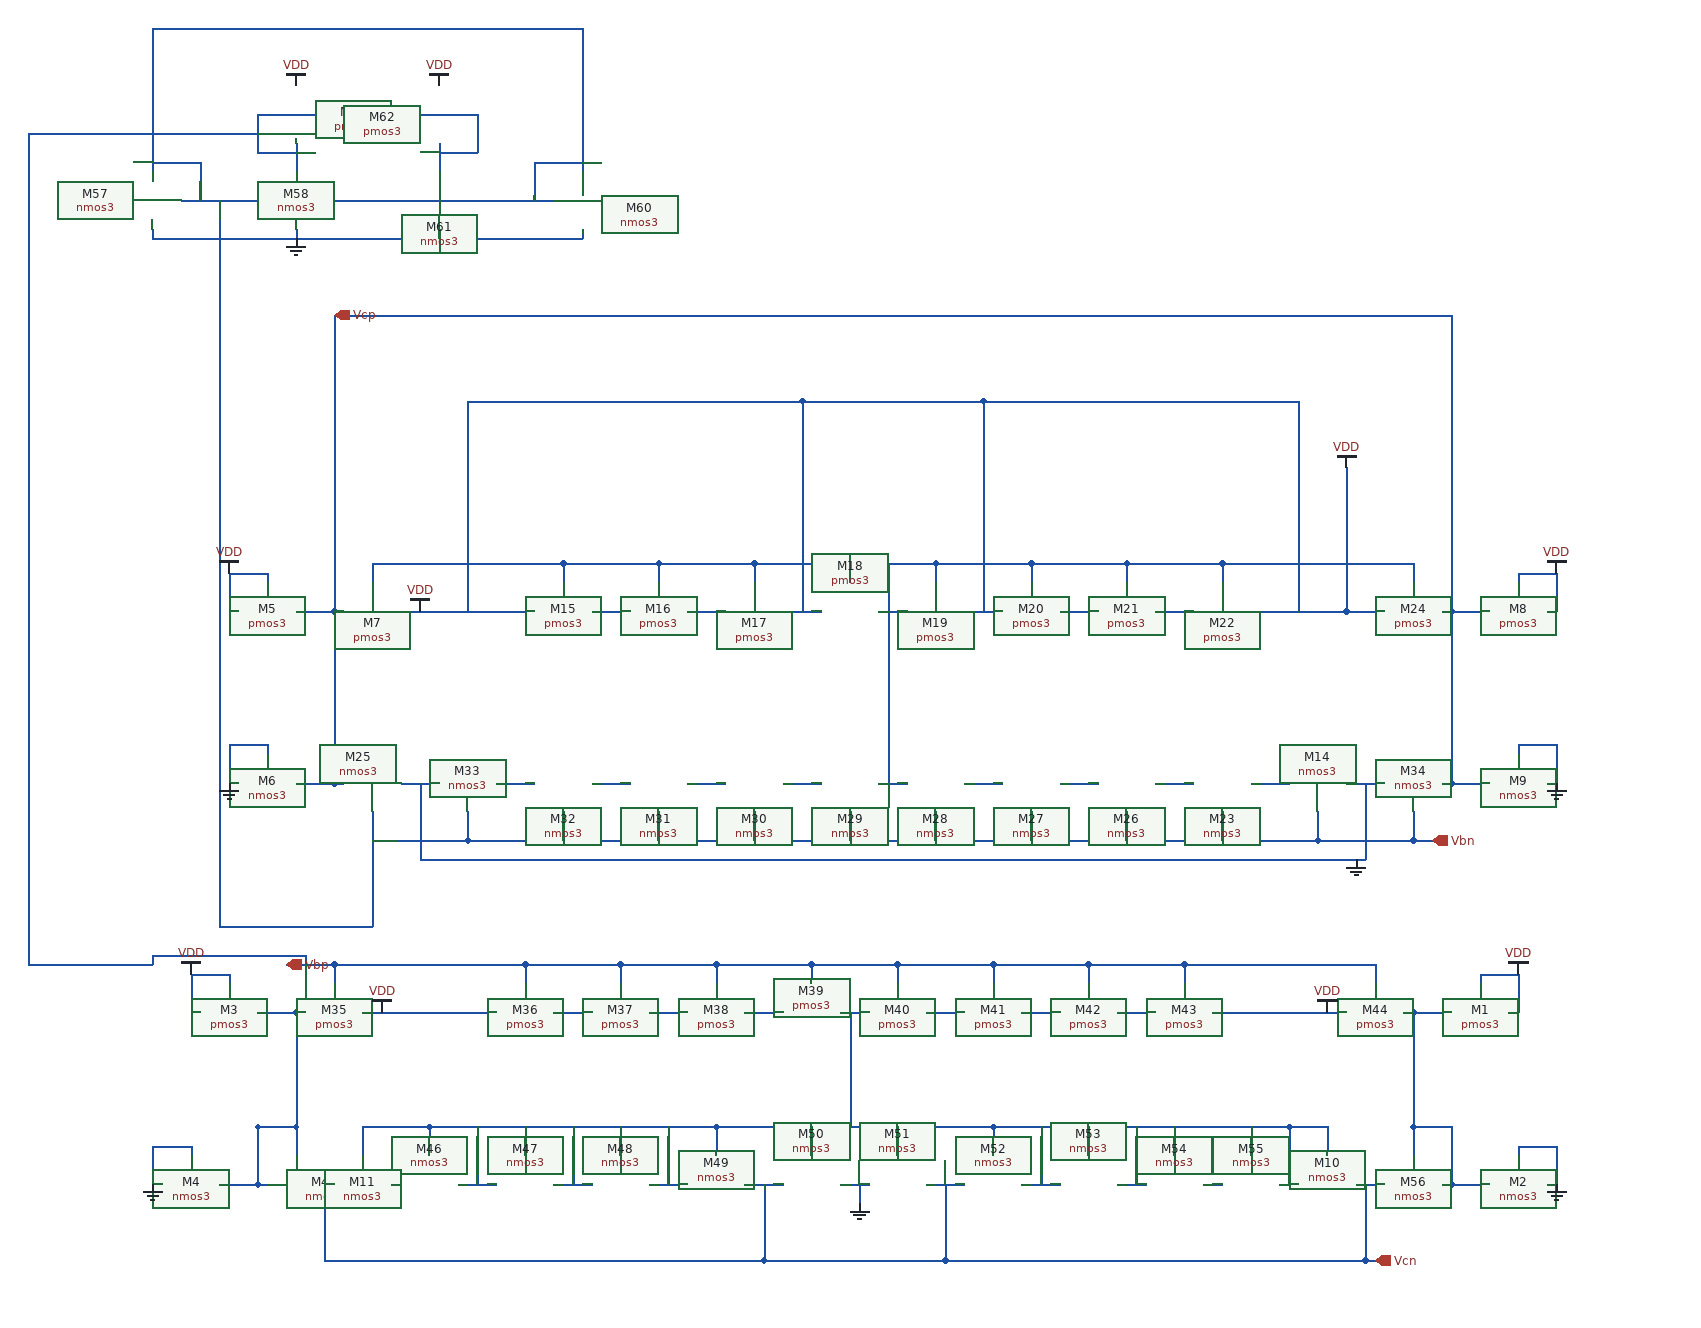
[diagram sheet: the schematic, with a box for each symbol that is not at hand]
v {xschem version=3.4.3 file_version=1.2
}
G {}
K {}
V {}
S {}
E {}
N 920 -40 960 -40 {
lab=VDD}
N 890 -90 890 -70 {
lab=VDD}
N 990 -90 1080 -90 {
lab=VDD}
N 1020 -40 1050 -40 {
lab=VDD}
N 1050 -40 1060 -40 {
lab=VDD}
N 1090 -90 1090 -70 {
lab=VDD}
N 1080 -90 1090 -90 {
lab=VDD}
N 1220 -40 1260 -40 {
lab=#net1}
N 1190 -90 1190 -70 {
lab=VDD}
N 1190 -90 1290 -90 {
lab=VDD}
N 1290 -90 1290 -70 {
lab=VDD}
N 1290 -90 1380 -90 {
lab=VDD}
N 1320 -40 1350 -40 {
lab=VDD}
N 1350 -40 1360 -40 {
lab=VDD}
N 1390 -90 1390 -70 {
lab=VDD}
N 1380 -90 1390 -90 {
lab=VDD}
N 1120 -40 1160 -40 {
lab=#net2}
N 1090 -90 1190 -90 {
lab=VDD}
N 1510 -40 1550 -40 {
lab=VDD}
N 1480 -90 1480 -70 {
lab=VDD}
N 1480 -90 1580 -90 {
lab=VDD}
N 1580 -90 1580 -70 {
lab=VDD}
N 1580 -90 1670 -90 {
lab=VDD}
N 1610 -40 1640 -40 {
lab=#net3}
N 1640 -40 1650 -40 {
lab=#net3}
N 1680 -90 1680 -70 {
lab=VDD}
N 1670 -90 1680 -90 {
lab=VDD}
N 1810 -40 1850 -40 {
lab=VDD}
N 1780 -90 1780 -70 {
lab=VDD}
N 1780 -90 1880 -90 {
lab=VDD}
N 1910 -40 1940 -40 {
lab=VDD}
N 1940 -40 1950 -40 {
lab=VDD}
N 1980 -90 1980 -70 {
lab=VDD}
N 1970 -90 1980 -90 {
lab=VDD}
N 1710 -40 1750 -40 {
lab=#net4}
N 1680 -90 1780 -90 {
lab=VDD}
N 1420 -40 1450 -40 {
lab=VDD}
N 1390 -90 1480 -90 {
lab=VDD}
N 1930 -90 1970 -90 {
lab=VDD}
N 890 -90 940 -90 {
lab=VDD}
N 1880 -90 1930 -90 {
lab=VDD}
N 940 -90 990 -90 {
lab=VDD}
N 960 -40 1020 -40 {
lab=VDD}
N 1850 -40 1910 -40 {
lab=VDD}
N 1220 140 1260 140 {
lab=#net5}
N 1120 140 1160 140 {
lab=#net6}
N 1020 140 1060 140 {
lab=#net7}
N 1320 140 1360 140 {
lab=#net8}
N 920 140 960 140 {
lab=GND}
N 940 140 940 220 {
lab=GND}
N 940 220 1340 220 {
lab=GND}
N 1810 140 1850 140 {
lab=#net9}
N 1710 140 1750 140 {
lab=#net10}
N 1610 140 1650 140 {
lab=#net11}
N 1910 140 1950 140 {
lab=GND}
N 1510 140 1550 140 {
lab=#net12}
N 1930 140 1930 220 {
lab=GND}
N 1420 140 1450 140 {
lab=VDD}
N 1340 220 1530 220 {
lab=GND}
N 2010 140 2020 140 {
lab=Vcp}
N 850 140 860 140 {
lab=Vcp}
N 850 -40 860 -40 {
lab=Vcp}
N 2010 -40 2020 -40 {
lab=Vcp}
N 880 380 920 380 {
lab=VDD}
N 850 330 850 350 {
lab=Vbp}
N 950 330 1040 330 {
lab=Vbp}
N 980 380 1010 380 {
lab=VDD}
N 1010 380 1020 380 {
lab=VDD}
N 1050 330 1050 350 {
lab=Vbp}
N 1040 330 1050 330 {
lab=Vbp}
N 1180 380 1220 380 {
lab=#net13}
N 1150 330 1150 350 {
lab=Vbp}
N 1150 330 1250 330 {
lab=Vbp}
N 1250 330 1250 350 {
lab=Vbp}
N 1250 330 1340 330 {
lab=Vbp}
N 1280 380 1310 380 {
lab=#net14}
N 1310 380 1320 380 {
lab=#net14}
N 1350 330 1350 350 {
lab=Vbp}
N 1340 330 1350 330 {
lab=Vbp}
N 1080 380 1120 380 {
lab=#net15}
N 1050 330 1150 330 {
lab=Vbp}
N 1470 380 1510 380 {
lab=#net16}
N 1440 330 1440 350 {
lab=Vbp}
N 1440 330 1540 330 {
lab=Vbp}
N 1540 330 1540 350 {
lab=Vbp}
N 1540 330 1630 330 {
lab=Vbp}
N 1570 380 1600 380 {
lab=#net17}
N 1600 380 1610 380 {
lab=#net17}
N 1640 330 1640 350 {
lab=Vbp}
N 1630 330 1640 330 {
lab=Vbp}
N 1770 380 1810 380 {
lab=VDD}
N 1740 330 1740 350 {
lab=Vbp}
N 1740 330 1840 330 {
lab=Vbp}
N 1870 380 1900 380 {
lab=VDD}
N 1900 380 1910 380 {
lab=VDD}
N 1940 330 1940 350 {
lab=Vbp}
N 1930 330 1940 330 {
lab=Vbp}
N 1670 380 1710 380 {
lab=#net18}
N 1640 330 1740 330 {
lab=Vbp}
N 1380 380 1410 380 {
lab=#net19}
N 1350 330 1440 330 {
lab=Vbp}
N 1890 330 1930 330 {
lab=Vbp}
N 850 330 900 330 {
lab=Vbp}
N 1840 330 1890 330 {
lab=Vbp}
N 900 330 950 330 {
lab=Vbp}
N 920 380 980 380 {
lab=VDD}
N 1810 380 1870 380 {
lab=VDD}
N 1180 560 1220 560 {
lab=#net19}
N 1080 560 1120 560 {
lab=#net19}
N 980 560 1020 560 {
lab=#net19}
N 1280 560 1320 560 {
lab=Vcn}
N 900 640 1300 640 {
lab=Vcn}
N 1300 560 1300 640 {
lab=Vcn}
N 950 500 950 530 {
lab=#net19}
N 950 500 1250 500 {
lab=#net19}
N 1250 500 1250 530 {
lab=#net19}
N 1570 560 1610 560 {
lab=#net19}
N 1470 560 1510 560 {
lab=Vcn}
N 1490 560 1490 640 {
lab=Vcn}
N 1490 640 1890 640 {
lab=Vcn}
N 1930 560 1930 640 {
lab=Vcn}
N 1540 500 1540 530 {
lab=#net19}
N 1380 560 1410 560 {
lab=GND}
N 1400 560 1400 580 {
lab=GND}
N 1300 640 1490 640 {
lab=Vcn}
N 1250 500 1540 500 {
lab=#net19}
N 1980 500 1980 530 {
lab=#net20}
N 1980 500 2020 500 {
lab=#net20}
N 2010 560 2020 560 {
lab=#net20}
N 2020 500 2020 560 {
lab=#net20}
N 810 500 810 530 {
lab=#net21}
N 770 500 810 500 {
lab=#net21}
N 770 560 780 560 {
lab=#net21}
N 770 500 770 560 {
lab=#net21}
N 1980 380 1980 500 {
lab=#net20}
N 810 380 820 380 {
lab=#net21}
N 810 380 810 500 {
lab=#net21}
N 1970 380 1980 380 {
lab=#net20}
N 1350 500 1350 530 {
lab=#net19}
N 1440 500 1440 530 {
lab=#net19}
N 1390 380 1390 500 {
lab=#net19}
N 800 330 850 330 {
lab=Vbp}
N 1930 640 1940 640 {
lab=Vcn}
N 660 -530 660 -500 {
lab=Vbn}
N 660 -440 660 -430 {
lab=GND}
N 810 -440 810 -430 {
lab=GND}
N 690 -470 780 -470 {
lab=Vbn}
N 710 -510 710 -470 {
lab=Vbn}
N 660 -510 710 -510 {
lab=Vbn}
N 810 -530 810 -500 {
lab=Vbp}
N 770 -520 810 -520 {
lab=Vbp}
N 770 -560 770 -520 {
lab=Vbp}
N 770 -560 780 -560 {
lab=Vbp}
N 1110 -530 1110 -500 {
lab=Vbn}
N 1110 -440 1110 -430 {
lab=GND}
N 960 -440 960 -430 {
lab=GND}
N 990 -470 1080 -470 {
lab=Vbn}
N 1060 -510 1060 -470 {
lab=Vbn}
N 1060 -510 1110 -510 {
lab=Vbn}
N 960 -530 960 -500 {
lab=Vbp}
N 960 -520 1000 -520 {
lab=Vbp}
N 1000 -560 1000 -520 {
lab=Vbp}
N 990 -560 1000 -560 {
lab=Vbp}
N 780 -560 990 -560 {
lab=Vbp}
N 780 -470 990 -470 {
lab=Vbn}
N 1110 -650 1110 -530 {
lab=Vbn}
N 660 -650 1110 -650 {
lab=Vbn}
N 660 -650 660 -640 {
lab=Vbn}
N 660 -640 660 -530 {
lab=Vbn}
N 660 -430 1110 -430 {
lab=GND}
N 730 -470 730 290 {
lab=Vbn}
N 2020 560 2060 560 {
lab=#net20}
N 1980 380 2020 380 {
lab=#net20}
N 2050 340 2050 350 {
lab=VDD}
N 2050 340 2090 340 {
lab=VDD}
N 2090 340 2090 380 {
lab=VDD}
N 2080 380 2090 380 {
lab=VDD}
N 2090 520 2090 530 {
lab=GND}
N 2090 520 2130 520 {
lab=GND}
N 2130 520 2130 560 {
lab=GND}
N 2120 560 2130 560 {
lab=GND}
N 770 500 770 560 {
lab=#net21}
N 810 380 810 500 {
lab=#net21}
N 730 560 770 560 {
lab=#net21}
N 770 380 810 380 {
lab=#net21}
N 740 340 740 350 {
lab=VDD}
N 700 340 740 340 {
lab=VDD}
N 700 340 700 380 {
lab=VDD}
N 700 380 710 380 {
lab=VDD}
N 700 520 700 530 {
lab=GND}
N 660 520 700 520 {
lab=GND}
N 660 520 660 560 {
lab=GND}
N 660 560 670 560 {
lab=GND}
N 850 80 850 140 {
lab=Vcp}
N 810 140 850 140 {
lab=Vcp}
N 810 -40 850 -40 {
lab=Vcp}
N 780 -80 780 -70 {
lab=VDD}
N 740 -80 780 -80 {
lab=VDD}
N 740 -80 740 -40 {
lab=VDD}
N 740 -40 750 -40 {
lab=VDD}
N 780 100 780 110 {
lab=GND}
N 740 100 780 100 {
lab=GND}
N 740 100 740 140 {
lab=GND}
N 740 140 750 140 {
lab=GND}
N 2020 -40 2020 80 {
lab=Vcp}
N 2020 140 2060 140 {
lab=Vcp}
N 2020 -40 2060 -40 {
lab=Vcp}
N 2090 -80 2090 -70 {
lab=VDD}
N 2090 -80 2130 -80 {
lab=VDD}
N 2130 -80 2130 -40 {
lab=VDD}
N 2120 -40 2130 -40 {
lab=VDD}
N 2090 100 2090 110 {
lab=GND}
N 2090 100 2130 100 {
lab=GND}
N 2130 100 2130 140 {
lab=GND}
N 2120 140 2130 140 {
lab=GND}
N 1000 500 1000 560 {
lab=#net19}
N 1050 500 1050 530 {
lab=#net19}
N 1150 500 1150 530 {
lab=#net19}
N 1100 500 1100 560 {
lab=#net19}
N 1200 500 1200 560 {
lab=#net19}
N 1640 500 1640 530 {
lab=#net19}
N 1590 500 1590 560 {
lab=#net19}
N 1690 500 1690 560 {
lab=#net19}
N 1810 500 1810 530 {
lab=#net19}
N 1540 500 1820 500 {
lab=#net19}
N 1850 500 1850 560 {
lab=#net19}
N 1850 500 1880 500 {
lab=#net19}
N 1820 500 1850 500 {
lab=#net19}
N 1890 640 1930 640 {
lab=Vcn}
N 840 640 900 640 {
lab=Vcn}
N 840 560 840 640 {
lab=Vcn}
N 1430 80 1430 140 {
lab=VDD}
N 990 200 1880 200 {
lab=Vbn}
N 1880 200 1980 200 {
lab=Vbn}
N 1980 200 2000 200 {
lab=Vbn}
N 1530 220 1930 220 {
lab=GND}
N 1430 -90 1430 80 {
lab=VDD}
N 1910 -190 1910 -40 {
lab=VDD}
N 990 -250 990 -40 {
lab=VDD}
N 1340 -260 1340 -40 {
lab=VDD}
N 990 -260 1340 -260 {
lab=VDD}
N 990 -260 990 -250 {
lab=VDD}
N 1530 -260 1530 -40 {
lab=VDD}
N 1530 -260 1860 -260 {
lab=VDD}
N 1860 -260 1860 -40 {
lab=VDD}
N 1340 -260 1530 -260 {
lab=VDD}
N 850 -350 850 -40 {
lab=Vcp}
N 850 -350 2010 -350 {
lab=Vcp}
N 2010 -350 2020 -350 {
lab=Vcp}
N 2020 -350 2020 -40 {
lab=Vcp}
N 890 170 890 240 {
lab=Vbn}
N 730 290 890 290 {
lab=Vbn}
N 530 -540 770 -540 {
lab=Vbp}
N 530 -540 530 330 {
lab=Vbp}
N 530 330 660 330 {
lab=Vbp}
N 660 320 660 330 {
lab=Vbp}
N 660 320 820 320 {
lab=Vbp}
N 820 320 820 330 {
lab=Vbp}
N 890 200 980 200 {
lab=Vbn}
N 980 200 990 200 {
lab=Vbn}
N 990 170 990 200 {
lab=Vbn}
N 1090 170 1090 200 {
lab=Vbn}
N 1190 170 1190 200 {
lab=Vbn}
N 1290 170 1290 200 {
lab=Vbn}
N 1390 170 1390 200 {
lab=Vbn}
N 1480 170 1480 200 {
lab=Vbn}
N 1580 170 1580 200 {
lab=Vbn}
N 1680 170 1680 200 {
lab=Vbn}
N 1780 170 1780 200 {
lab=Vbn}
N 1880 170 1880 200 {
lab=Vbn}
N 1980 170 1980 200 {
lab=Vbn}
N 850 -40 850 80 {
lab=Vcp}
N 2020 80 2020 140 {
lab=Vcp}
N 840 560 850 560 {
lab=Vcn}
N 910 560 920 560 {
lab=#net22}
N 880 500 880 530 {
lab=#net19}
N 880 500 950 500 {
lab=#net19}
N 1670 560 1700 560 {
lab=#net19}
N 1730 500 1730 530 {
lab=#net19}
N 1920 560 1950 560 {
lab=Vcn}
N 1890 500 1890 530 {
lab=#net19}
N 1880 500 1890 500 {
lab=#net19}
N 1840 560 1860 560 {
lab=#net19}
N 1760 560 1780 560 {
lab=#net23}
N 890 240 890 290 {
lab=Vbn}
C {madvlsi/pmos3.sym} 890 -40 1 0 {name=M7
L=0.5
W=12
body=VDD
nf=1
mult=1
ad="'int((nf+1)/2) * W/nf * 0.29'" 
pd="'2*int((nf+1)/2) * (W/nf + 0.29)'"
as="'int((nf+2)/2) * W/nf * 0.29'" 
ps="'2*int((nf+2)/2) * (W/nf + 0.29)'"
nrd="'0.29 / W'" nrs="'0.29 / W'"
sa=0 sb=0 sd=0
model=pfet_01v8
spiceprefix=X
}
C {madvlsi/pmos3.sym} 1090 -40 1 0 {name=M15
L=0.5
W=12
body=VDD
nf=1
mult=1
ad="'int((nf+1)/2) * W/nf * 0.29'" 
pd="'2*int((nf+1)/2) * (W/nf + 0.29)'"
as="'int((nf+2)/2) * W/nf * 0.29'" 
ps="'2*int((nf+2)/2) * (W/nf + 0.29)'"
nrd="'0.29 / W'" nrs="'0.29 / W'"
sa=0 sb=0 sd=0
model=pfet_01v8
spiceprefix=X
}
C {madvlsi/pmos3.sym} 1190 -40 1 0 {name=M16
L=0.5
W=12
body=VDD
nf=1
mult=1
ad="'int((nf+1)/2) * W/nf * 0.29'" 
pd="'2*int((nf+1)/2) * (W/nf + 0.29)'"
as="'int((nf+2)/2) * W/nf * 0.29'" 
ps="'2*int((nf+2)/2) * (W/nf + 0.29)'"
nrd="'0.29 / W'" nrs="'0.29 / W'"
sa=0 sb=0 sd=0
model=pfet_01v8
spiceprefix=X
}
C {madvlsi/pmos3.sym} 1290 -40 1 0 {name=M17
L=0.5
W=12
body=VDD
nf=1
mult=1
ad="'int((nf+1)/2) * W/nf * 0.29'" 
pd="'2*int((nf+1)/2) * (W/nf + 0.29)'"
as="'int((nf+2)/2) * W/nf * 0.29'" 
ps="'2*int((nf+2)/2) * (W/nf + 0.29)'"
nrd="'0.29 / W'" nrs="'0.29 / W'"
sa=0 sb=0 sd=0
model=pfet_01v8
spiceprefix=X
}
C {madvlsi/pmos3.sym} 1390 -40 1 0 {name=M18
L=0.5
W=12
body=VDD
nf=1
mult=1
ad="'int((nf+1)/2) * W/nf * 0.29'" 
pd="'2*int((nf+1)/2) * (W/nf + 0.29)'"
as="'int((nf+2)/2) * W/nf * 0.29'" 
ps="'2*int((nf+2)/2) * (W/nf + 0.29)'"
nrd="'0.29 / W'" nrs="'0.29 / W'"
sa=0 sb=0 sd=0
model=pfet_01v8
spiceprefix=X
}
C {madvlsi/pmos3.sym} 1480 -40 1 0 {name=M19
L=0.5
W=12
body=VDD
nf=1
mult=1
ad="'int((nf+1)/2) * W/nf * 0.29'" 
pd="'2*int((nf+1)/2) * (W/nf + 0.29)'"
as="'int((nf+2)/2) * W/nf * 0.29'" 
ps="'2*int((nf+2)/2) * (W/nf + 0.29)'"
nrd="'0.29 / W'" nrs="'0.29 / W'"
sa=0 sb=0 sd=0
model=pfet_01v8
spiceprefix=X
}
C {madvlsi/pmos3.sym} 1580 -40 1 0 {name=M20
L=0.5
W=12
body=VDD
nf=1
mult=1
ad="'int((nf+1)/2) * W/nf * 0.29'" 
pd="'2*int((nf+1)/2) * (W/nf + 0.29)'"
as="'int((nf+2)/2) * W/nf * 0.29'" 
ps="'2*int((nf+2)/2) * (W/nf + 0.29)'"
nrd="'0.29 / W'" nrs="'0.29 / W'"
sa=0 sb=0 sd=0
model=pfet_01v8
spiceprefix=X
}
C {madvlsi/pmos3.sym} 1680 -40 1 0 {name=M21
L=0.5
W=12
body=VDD
nf=1
mult=1
ad="'int((nf+1)/2) * W/nf * 0.29'" 
pd="'2*int((nf+1)/2) * (W/nf + 0.29)'"
as="'int((nf+2)/2) * W/nf * 0.29'" 
ps="'2*int((nf+2)/2) * (W/nf + 0.29)'"
nrd="'0.29 / W'" nrs="'0.29 / W'"
sa=0 sb=0 sd=0
model=pfet_01v8
spiceprefix=X
}
C {madvlsi/pmos3.sym} 1780 -40 1 0 {name=M22
L=0.5
W=12
body=VDD
nf=1
mult=1
ad="'int((nf+1)/2) * W/nf * 0.29'" 
pd="'2*int((nf+1)/2) * (W/nf + 0.29)'"
as="'int((nf+2)/2) * W/nf * 0.29'" 
ps="'2*int((nf+2)/2) * (W/nf + 0.29)'"
nrd="'0.29 / W'" nrs="'0.29 / W'"
sa=0 sb=0 sd=0
model=pfet_01v8
spiceprefix=X
}
C {madvlsi/pmos3.sym} 1980 -40 1 0 {name=M24
L=0.5
W=12
body=VDD
nf=1
mult=1
ad="'int((nf+1)/2) * W/nf * 0.29'" 
pd="'2*int((nf+1)/2) * (W/nf + 0.29)'"
as="'int((nf+2)/2) * W/nf * 0.29'" 
ps="'2*int((nf+2)/2) * (W/nf + 0.29)'"
nrd="'0.29 / W'" nrs="'0.29 / W'"
sa=0 sb=0 sd=0
model=pfet_01v8
spiceprefix=X
}
C {madvlsi/vdd.sym} 940 -40 0 0 {name=l9 lab=VDD}
C {madvlsi/nmos3.sym} 890 140 3 0 {name=M25
L=0.5
W=12
body=GND
nf=1
mult=1
ad="'int((nf+1)/2) * W/nf * 0.29'" 
pd="'2*int((nf+1)/2) * (W/nf + 0.29)'"
as="'int((nf+2)/2) * W/nf * 0.29'" 
ps="'2*int((nf+2)/2) * (W/nf + 0.29)'"
nrd="'0.29 / W'" nrs="'0.29 / W'"
sa=0 sb=0 sd=0
model=nfet_01v8
spiceprefix=X
}
C {madvlsi/nmos3.sym} 1880 140 3 0 {name=M14
L=0.5
W=12
body=GND
nf=1
mult=1
ad="'int((nf+1)/2) * W/nf * 0.29'" 
pd="'2*int((nf+1)/2) * (W/nf + 0.29)'"
as="'int((nf+2)/2) * W/nf * 0.29'" 
ps="'2*int((nf+2)/2) * (W/nf + 0.29)'"
nrd="'0.29 / W'" nrs="'0.29 / W'"
sa=0 sb=0 sd=0
model=nfet_01v8
spiceprefix=X
}
C {madvlsi/nmos3.sym} 1780 140 3 0 {name=M23
L=0.5
W=12
body=GND
nf=1
mult=1
ad="'int((nf+1)/2) * W/nf * 0.29'" 
pd="'2*int((nf+1)/2) * (W/nf + 0.29)'"
as="'int((nf+2)/2) * W/nf * 0.29'" 
ps="'2*int((nf+2)/2) * (W/nf + 0.29)'"
nrd="'0.29 / W'" nrs="'0.29 / W'"
sa=0 sb=0 sd=0
model=nfet_01v8
spiceprefix=X
}
C {madvlsi/nmos3.sym} 1680 140 3 0 {name=M26
L=0.5
W=12
body=GND
nf=1
mult=1
ad="'int((nf+1)/2) * W/nf * 0.29'" 
pd="'2*int((nf+1)/2) * (W/nf + 0.29)'"
as="'int((nf+2)/2) * W/nf * 0.29'" 
ps="'2*int((nf+2)/2) * (W/nf + 0.29)'"
nrd="'0.29 / W'" nrs="'0.29 / W'"
sa=0 sb=0 sd=0
model=nfet_01v8
spiceprefix=X
}
C {madvlsi/nmos3.sym} 1580 140 3 0 {name=M27
L=0.5
W=12
body=GND
nf=1
mult=1
ad="'int((nf+1)/2) * W/nf * 0.29'" 
pd="'2*int((nf+1)/2) * (W/nf + 0.29)'"
as="'int((nf+2)/2) * W/nf * 0.29'" 
ps="'2*int((nf+2)/2) * (W/nf + 0.29)'"
nrd="'0.29 / W'" nrs="'0.29 / W'"
sa=0 sb=0 sd=0
model=nfet_01v8
spiceprefix=X
}
C {madvlsi/nmos3.sym} 1480 140 3 0 {name=M28
L=0.5
W=12
body=GND
nf=1
mult=1
ad="'int((nf+1)/2) * W/nf * 0.29'" 
pd="'2*int((nf+1)/2) * (W/nf + 0.29)'"
as="'int((nf+2)/2) * W/nf * 0.29'" 
ps="'2*int((nf+2)/2) * (W/nf + 0.29)'"
nrd="'0.29 / W'" nrs="'0.29 / W'"
sa=0 sb=0 sd=0
model=nfet_01v8
spiceprefix=X
}
C {madvlsi/nmos3.sym} 1390 140 3 0 {name=M29
L=0.5
W=12
body=GND
nf=1
mult=1
ad="'int((nf+1)/2) * W/nf * 0.29'" 
pd="'2*int((nf+1)/2) * (W/nf + 0.29)'"
as="'int((nf+2)/2) * W/nf * 0.29'" 
ps="'2*int((nf+2)/2) * (W/nf + 0.29)'"
nrd="'0.29 / W'" nrs="'0.29 / W'"
sa=0 sb=0 sd=0
model=nfet_01v8
spiceprefix=X
}
C {madvlsi/nmos3.sym} 1290 140 3 0 {name=M30
L=0.5
W=12
body=GND
nf=1
mult=1
ad="'int((nf+1)/2) * W/nf * 0.29'" 
pd="'2*int((nf+1)/2) * (W/nf + 0.29)'"
as="'int((nf+2)/2) * W/nf * 0.29'" 
ps="'2*int((nf+2)/2) * (W/nf + 0.29)'"
nrd="'0.29 / W'" nrs="'0.29 / W'"
sa=0 sb=0 sd=0
model=nfet_01v8
spiceprefix=X
}
C {madvlsi/nmos3.sym} 1190 140 3 0 {name=M31
L=0.5
W=12
body=GND
nf=1
mult=1
ad="'int((nf+1)/2) * W/nf * 0.29'" 
pd="'2*int((nf+1)/2) * (W/nf + 0.29)'"
as="'int((nf+2)/2) * W/nf * 0.29'" 
ps="'2*int((nf+2)/2) * (W/nf + 0.29)'"
nrd="'0.29 / W'" nrs="'0.29 / W'"
sa=0 sb=0 sd=0
model=nfet_01v8
spiceprefix=X
}
C {madvlsi/nmos3.sym} 1090 140 3 0 {name=M32
L=0.5
W=12
body=GND
nf=1
mult=1
ad="'int((nf+1)/2) * W/nf * 0.29'" 
pd="'2*int((nf+1)/2) * (W/nf + 0.29)'"
as="'int((nf+2)/2) * W/nf * 0.29'" 
ps="'2*int((nf+2)/2) * (W/nf + 0.29)'"
nrd="'0.29 / W'" nrs="'0.29 / W'"
sa=0 sb=0 sd=0
model=nfet_01v8
spiceprefix=X
}
C {madvlsi/nmos3.sym} 990 140 3 0 {name=M33
L=0.5
W=12
body=GND
nf=1
mult=1
ad="'int((nf+1)/2) * W/nf * 0.29'" 
pd="'2*int((nf+1)/2) * (W/nf + 0.29)'"
as="'int((nf+2)/2) * W/nf * 0.29'" 
ps="'2*int((nf+2)/2) * (W/nf + 0.29)'"
nrd="'0.29 / W'" nrs="'0.29 / W'"
sa=0 sb=0 sd=0
model=nfet_01v8
spiceprefix=X
}
C {madvlsi/nmos3.sym} 1980 140 3 0 {name=M34
L=0.5
W=12
body=GND
nf=1
mult=1
ad="'int((nf+1)/2) * W/nf * 0.29'" 
pd="'2*int((nf+1)/2) * (W/nf + 0.29)'"
as="'int((nf+2)/2) * W/nf * 0.29'" 
ps="'2*int((nf+2)/2) * (W/nf + 0.29)'"
nrd="'0.29 / W'" nrs="'0.29 / W'"
sa=0 sb=0 sd=0
model=nfet_01v8
spiceprefix=X
}
C {devices/opin.sym} 800 330 2 0 {name=p1 lab=Vbp}
C {devices/opin.sym} 1940 640 0 0 {name=p3 lab=Vcn}
C {madvlsi/pmos3.sym} 850 380 1 0 {name=M35
L=0.5
W=12
body=VDD
nf=1
mult=1
ad="'int((nf+1)/2) * W/nf * 0.29'" 
pd="'2*int((nf+1)/2) * (W/nf + 0.29)'"
as="'int((nf+2)/2) * W/nf * 0.29'" 
ps="'2*int((nf+2)/2) * (W/nf + 0.29)'"
nrd="'0.29 / W'" nrs="'0.29 / W'"
sa=0 sb=0 sd=0
model=pfet_01v8
spiceprefix=X
}
C {madvlsi/pmos3.sym} 1050 380 1 0 {name=M36
L=0.5
W=12
body=VDD
nf=1
mult=1
ad="'int((nf+1)/2) * W/nf * 0.29'" 
pd="'2*int((nf+1)/2) * (W/nf + 0.29)'"
as="'int((nf+2)/2) * W/nf * 0.29'" 
ps="'2*int((nf+2)/2) * (W/nf + 0.29)'"
nrd="'0.29 / W'" nrs="'0.29 / W'"
sa=0 sb=0 sd=0
model=pfet_01v8
spiceprefix=X
}
C {madvlsi/pmos3.sym} 1150 380 1 0 {name=M37
L=0.5
W=12
body=VDD
nf=1
mult=1
ad="'int((nf+1)/2) * W/nf * 0.29'" 
pd="'2*int((nf+1)/2) * (W/nf + 0.29)'"
as="'int((nf+2)/2) * W/nf * 0.29'" 
ps="'2*int((nf+2)/2) * (W/nf + 0.29)'"
nrd="'0.29 / W'" nrs="'0.29 / W'"
sa=0 sb=0 sd=0
model=pfet_01v8
spiceprefix=X
}
C {madvlsi/pmos3.sym} 1250 380 1 0 {name=M38
L=0.5
W=12
body=VDD
nf=1
mult=1
ad="'int((nf+1)/2) * W/nf * 0.29'" 
pd="'2*int((nf+1)/2) * (W/nf + 0.29)'"
as="'int((nf+2)/2) * W/nf * 0.29'" 
ps="'2*int((nf+2)/2) * (W/nf + 0.29)'"
nrd="'0.29 / W'" nrs="'0.29 / W'"
sa=0 sb=0 sd=0
model=pfet_01v8
spiceprefix=X
}
C {madvlsi/pmos3.sym} 1350 380 1 0 {name=M39
L=0.5
W=12
body=VDD
nf=1
mult=1
ad="'int((nf+1)/2) * W/nf * 0.29'" 
pd="'2*int((nf+1)/2) * (W/nf + 0.29)'"
as="'int((nf+2)/2) * W/nf * 0.29'" 
ps="'2*int((nf+2)/2) * (W/nf + 0.29)'"
nrd="'0.29 / W'" nrs="'0.29 / W'"
sa=0 sb=0 sd=0
model=pfet_01v8
spiceprefix=X
}
C {madvlsi/pmos3.sym} 1440 380 1 0 {name=M40
L=0.5
W=12
body=VDD
nf=1
mult=1
ad="'int((nf+1)/2) * W/nf * 0.29'" 
pd="'2*int((nf+1)/2) * (W/nf + 0.29)'"
as="'int((nf+2)/2) * W/nf * 0.29'" 
ps="'2*int((nf+2)/2) * (W/nf + 0.29)'"
nrd="'0.29 / W'" nrs="'0.29 / W'"
sa=0 sb=0 sd=0
model=pfet_01v8
spiceprefix=X
}
C {madvlsi/pmos3.sym} 1540 380 1 0 {name=M41
L=0.5
W=12
body=VDD
nf=1
mult=1
ad="'int((nf+1)/2) * W/nf * 0.29'" 
pd="'2*int((nf+1)/2) * (W/nf + 0.29)'"
as="'int((nf+2)/2) * W/nf * 0.29'" 
ps="'2*int((nf+2)/2) * (W/nf + 0.29)'"
nrd="'0.29 / W'" nrs="'0.29 / W'"
sa=0 sb=0 sd=0
model=pfet_01v8
spiceprefix=X
}
C {madvlsi/pmos3.sym} 1640 380 1 0 {name=M42
L=0.5
W=12
body=VDD
nf=1
mult=1
ad="'int((nf+1)/2) * W/nf * 0.29'" 
pd="'2*int((nf+1)/2) * (W/nf + 0.29)'"
as="'int((nf+2)/2) * W/nf * 0.29'" 
ps="'2*int((nf+2)/2) * (W/nf + 0.29)'"
nrd="'0.29 / W'" nrs="'0.29 / W'"
sa=0 sb=0 sd=0
model=pfet_01v8
spiceprefix=X
}
C {madvlsi/pmos3.sym} 1740 380 1 0 {name=M43
L=0.5
W=12
body=VDD
nf=1
mult=1
ad="'int((nf+1)/2) * W/nf * 0.29'" 
pd="'2*int((nf+1)/2) * (W/nf + 0.29)'"
as="'int((nf+2)/2) * W/nf * 0.29'" 
ps="'2*int((nf+2)/2) * (W/nf + 0.29)'"
nrd="'0.29 / W'" nrs="'0.29 / W'"
sa=0 sb=0 sd=0
model=pfet_01v8
spiceprefix=X
}
C {madvlsi/pmos3.sym} 1940 380 1 0 {name=M44
L=0.5
W=12
body=VDD
nf=1
mult=1
ad="'int((nf+1)/2) * W/nf * 0.29'" 
pd="'2*int((nf+1)/2) * (W/nf + 0.29)'"
as="'int((nf+2)/2) * W/nf * 0.29'" 
ps="'2*int((nf+2)/2) * (W/nf + 0.29)'"
nrd="'0.29 / W'" nrs="'0.29 / W'"
sa=0 sb=0 sd=0
model=pfet_01v8
spiceprefix=X
}
C {madvlsi/vdd.sym} 900 380 0 0 {name=l12 lab=VDD}
C {madvlsi/vdd.sym} 1890 380 0 0 {name=l13 lab=VDD}
C {madvlsi/nmos3.sym} 810 560 1 0 {name=M45
L=0.5
W=12
body=GND
nf=1
mult=1
ad="'int((nf+1)/2) * W/nf * 0.29'" 
pd="'2*int((nf+1)/2) * (W/nf + 0.29)'"
as="'int((nf+2)/2) * W/nf * 0.29'" 
ps="'2*int((nf+2)/2) * (W/nf + 0.29)'"
nrd="'0.29 / W'" nrs="'0.29 / W'"
sa=0 sb=0 sd=0
model=nfet_01v8
spiceprefix=X
}
C {madvlsi/nmos3.sym} 950 560 1 0 {name=M46
L=0.5
W=12
body=GND
nf=1
mult=1
ad="'int((nf+1)/2) * W/nf * 0.29'" 
pd="'2*int((nf+1)/2) * (W/nf + 0.29)'"
as="'int((nf+2)/2) * W/nf * 0.29'" 
ps="'2*int((nf+2)/2) * (W/nf + 0.29)'"
nrd="'0.29 / W'" nrs="'0.29 / W'"
sa=0 sb=0 sd=0
model=nfet_01v8
spiceprefix=X
}
C {madvlsi/nmos3.sym} 1050 560 1 0 {name=M47
L=0.5
W=12
body=GND
nf=1
mult=1
ad="'int((nf+1)/2) * W/nf * 0.29'" 
pd="'2*int((nf+1)/2) * (W/nf + 0.29)'"
as="'int((nf+2)/2) * W/nf * 0.29'" 
ps="'2*int((nf+2)/2) * (W/nf + 0.29)'"
nrd="'0.29 / W'" nrs="'0.29 / W'"
sa=0 sb=0 sd=0
model=nfet_01v8
spiceprefix=X
}
C {madvlsi/nmos3.sym} 1150 560 1 0 {name=M48
L=0.5
W=12
body=GND
nf=1
mult=1
ad="'int((nf+1)/2) * W/nf * 0.29'" 
pd="'2*int((nf+1)/2) * (W/nf + 0.29)'"
as="'int((nf+2)/2) * W/nf * 0.29'" 
ps="'2*int((nf+2)/2) * (W/nf + 0.29)'"
nrd="'0.29 / W'" nrs="'0.29 / W'"
sa=0 sb=0 sd=0
model=nfet_01v8
spiceprefix=X
}
C {madvlsi/nmos3.sym} 1250 560 1 0 {name=M49
L=0.5
W=12
body=GND
nf=1
mult=1
ad="'int((nf+1)/2) * W/nf * 0.29'" 
pd="'2*int((nf+1)/2) * (W/nf + 0.29)'"
as="'int((nf+2)/2) * W/nf * 0.29'" 
ps="'2*int((nf+2)/2) * (W/nf + 0.29)'"
nrd="'0.29 / W'" nrs="'0.29 / W'"
sa=0 sb=0 sd=0
model=nfet_01v8
spiceprefix=X
}
C {madvlsi/nmos3.sym} 1350 560 1 0 {name=M50
L=0.5
W=12
body=GND
nf=1
mult=1
ad="'int((nf+1)/2) * W/nf * 0.29'" 
pd="'2*int((nf+1)/2) * (W/nf + 0.29)'"
as="'int((nf+2)/2) * W/nf * 0.29'" 
ps="'2*int((nf+2)/2) * (W/nf + 0.29)'"
nrd="'0.29 / W'" nrs="'0.29 / W'"
sa=0 sb=0 sd=0
model=nfet_01v8
spiceprefix=X
}
C {madvlsi/nmos3.sym} 1440 560 1 0 {name=M51
L=0.5
W=12
body=GND
nf=1
mult=1
ad="'int((nf+1)/2) * W/nf * 0.29'" 
pd="'2*int((nf+1)/2) * (W/nf + 0.29)'"
as="'int((nf+2)/2) * W/nf * 0.29'" 
ps="'2*int((nf+2)/2) * (W/nf + 0.29)'"
nrd="'0.29 / W'" nrs="'0.29 / W'"
sa=0 sb=0 sd=0
model=nfet_01v8
spiceprefix=X
}
C {madvlsi/nmos3.sym} 1540 560 1 0 {name=M52
L=0.5
W=12
body=GND
nf=1
mult=1
ad="'int((nf+1)/2) * W/nf * 0.29'" 
pd="'2*int((nf+1)/2) * (W/nf + 0.29)'"
as="'int((nf+2)/2) * W/nf * 0.29'" 
ps="'2*int((nf+2)/2) * (W/nf + 0.29)'"
nrd="'0.29 / W'" nrs="'0.29 / W'"
sa=0 sb=0 sd=0
model=nfet_01v8
spiceprefix=X
}
C {madvlsi/nmos3.sym} 1640 560 1 0 {name=M53
L=0.5
W=12
body=GND
nf=1
mult=1
ad="'int((nf+1)/2) * W/nf * 0.29'" 
pd="'2*int((nf+1)/2) * (W/nf + 0.29)'"
as="'int((nf+2)/2) * W/nf * 0.29'" 
ps="'2*int((nf+2)/2) * (W/nf + 0.29)'"
nrd="'0.29 / W'" nrs="'0.29 / W'"
sa=0 sb=0 sd=0
model=nfet_01v8
spiceprefix=X
}
C {madvlsi/nmos3.sym} 1730 560 1 0 {name=M54
L=0.5
W=12
body=GND
nf=1
mult=1
ad="'int((nf+1)/2) * W/nf * 0.29'" 
pd="'2*int((nf+1)/2) * (W/nf + 0.29)'"
as="'int((nf+2)/2) * W/nf * 0.29'" 
ps="'2*int((nf+2)/2) * (W/nf + 0.29)'"
nrd="'0.29 / W'" nrs="'0.29 / W'"
sa=0 sb=0 sd=0
model=nfet_01v8
spiceprefix=X
}
C {madvlsi/nmos3.sym} 1810 560 1 0 {name=M55
L=0.5
W=12
body=GND
nf=1
mult=1
ad="'int((nf+1)/2) * W/nf * 0.29'" 
pd="'2*int((nf+1)/2) * (W/nf + 0.29)'"
as="'int((nf+2)/2) * W/nf * 0.29'" 
ps="'2*int((nf+2)/2) * (W/nf + 0.29)'"
nrd="'0.29 / W'" nrs="'0.29 / W'"
sa=0 sb=0 sd=0
model=nfet_01v8
spiceprefix=X
}
C {madvlsi/nmos3.sym} 1980 560 1 0 {name=M56
L=0.5
W=12
body=GND
nf=1
mult=1
ad="'int((nf+1)/2) * W/nf * 0.29'" 
pd="'2*int((nf+1)/2) * (W/nf + 0.29)'"
as="'int((nf+2)/2) * W/nf * 0.29'" 
ps="'2*int((nf+2)/2) * (W/nf + 0.29)'"
nrd="'0.29 / W'" nrs="'0.29 / W'"
sa=0 sb=0 sd=0
model=nfet_01v8
spiceprefix=X
}
C {madvlsi/gnd.sym} 1400 580 0 0 {name=l14 lab=GND}
C {devices/opin.sym} 850 -350 2 0 {name=p7 lab=Vcp}
C {devices/opin.sym} 2000 200 0 0 {name=p8 lab=Vbn}
C {madvlsi/nmos3.sym} 660 -470 2 0 {name=M57
L=0.5
W=12
body=GND
nf=1
mult=1
ad="'int((nf+1)/2) * W/nf * 0.29'" 
pd="'2*int((nf+1)/2) * (W/nf + 0.29)'"
as="'int((nf+2)/2) * W/nf * 0.29'" 
ps="'2*int((nf+2)/2) * (W/nf + 0.29)'"
nrd="'0.29 / W'" nrs="'0.29 / W'"
sa=0 sb=0 sd=0
model=nfet_01v8
spiceprefix=X
}
C {madvlsi/nmos3.sym} 810 -470 0 0 {name=M58
L=0.5
W=12
body=GND
nf=1
mult=1
ad="'int((nf+1)/2) * W/nf * 0.29'" 
pd="'2*int((nf+1)/2) * (W/nf + 0.29)'"
as="'int((nf+2)/2) * W/nf * 0.29'" 
ps="'2*int((nf+2)/2) * (W/nf + 0.29)'"
nrd="'0.29 / W'" nrs="'0.29 / W'"
sa=0 sb=0 sd=0
model=nfet_01v8
spiceprefix=X
}
C {madvlsi/gnd.sym} 810 -430 0 0 {name=l16 lab=GND}
C {madvlsi/pmos3.sym} 810 -560 0 0 {name=M59
L=0.5
W=12
body=VDD
nf=1
mult=1
ad="'int((nf+1)/2) * W/nf * 0.29'" 
pd="'2*int((nf+1)/2) * (W/nf + 0.29)'"
as="'int((nf+2)/2) * W/nf * 0.29'" 
ps="'2*int((nf+2)/2) * (W/nf + 0.29)'"
nrd="'0.29 / W'" nrs="'0.29 / W'"
sa=0 sb=0 sd=0
model=pfet_01v8
spiceprefix=X
}
C {madvlsi/vdd.sym} 810 -590 0 0 {name=l17 lab=VDD}
C {madvlsi/nmos3.sym} 1110 -470 2 1 {name=M60
L=0.5
W=12
body=GND
nf=1
mult=1
ad="'int((nf+1)/2) * W/nf * 0.29'" 
pd="'2*int((nf+1)/2) * (W/nf + 0.29)'"
as="'int((nf+2)/2) * W/nf * 0.29'" 
ps="'2*int((nf+2)/2) * (W/nf + 0.29)'"
nrd="'0.29 / W'" nrs="'0.29 / W'"
sa=0 sb=0 sd=0
model=nfet_01v8
spiceprefix=X
}
C {madvlsi/nmos3.sym} 960 -470 0 1 {name=M61
L=0.5
W=12
body=GND
nf=1
mult=1
ad="'int((nf+1)/2) * W/nf * 0.29'" 
pd="'2*int((nf+1)/2) * (W/nf + 0.29)'"
as="'int((nf+2)/2) * W/nf * 0.29'" 
ps="'2*int((nf+2)/2) * (W/nf + 0.29)'"
nrd="'0.29 / W'" nrs="'0.29 / W'"
sa=0 sb=0 sd=0
model=nfet_01v8
spiceprefix=X
}
C {madvlsi/pmos3.sym} 960 -560 0 1 {name=M62
L=0.5
W=12
body=VDD
nf=1
mult=1
ad="'int((nf+1)/2) * W/nf * 0.29'" 
pd="'2*int((nf+1)/2) * (W/nf + 0.29)'"
as="'int((nf+2)/2) * W/nf * 0.29'" 
ps="'2*int((nf+2)/2) * (W/nf + 0.29)'"
nrd="'0.29 / W'" nrs="'0.29 / W'"
sa=0 sb=0 sd=0
model=pfet_01v8
spiceprefix=X
}
C {madvlsi/vdd.sym} 960 -590 0 1 {name=l21 lab=VDD}
C {madvlsi/pmos3.sym} 2050 380 1 0 {name=M1
L=0.5
W=12
body=VDD
nf=1
mult=1
ad="'int((nf+1)/2) * W/nf * 0.29'" 
pd="'2*int((nf+1)/2) * (W/nf + 0.29)'"
as="'int((nf+2)/2) * W/nf * 0.29'" 
ps="'2*int((nf+2)/2) * (W/nf + 0.29)'"
nrd="'0.29 / W'" nrs="'0.29 / W'"
sa=0 sb=0 sd=0
model=pfet_01v8
spiceprefix=X
}
C {madvlsi/nmos3.sym} 2090 560 1 0 {name=M2
L=0.5
W=12
body=GND
nf=1
mult=1
ad="'int((nf+1)/2) * W/nf * 0.29'" 
pd="'2*int((nf+1)/2) * (W/nf + 0.29)'"
as="'int((nf+2)/2) * W/nf * 0.29'" 
ps="'2*int((nf+2)/2) * (W/nf + 0.29)'"
nrd="'0.29 / W'" nrs="'0.29 / W'"
sa=0 sb=0 sd=0
model=nfet_01v8
spiceprefix=X
}
C {madvlsi/vdd.sym} 2090 340 0 0 {name=l1 lab=VDD}
C {madvlsi/gnd.sym} 2130 560 0 0 {name=l2 lab=GND}
C {madvlsi/pmos3.sym} 740 380 3 1 {name=M3
L=0.5
W=12
body=VDD
nf=1
mult=1
ad="'int((nf+1)/2) * W/nf * 0.29'" 
pd="'2*int((nf+1)/2) * (W/nf + 0.29)'"
as="'int((nf+2)/2) * W/nf * 0.29'" 
ps="'2*int((nf+2)/2) * (W/nf + 0.29)'"
nrd="'0.29 / W'" nrs="'0.29 / W'"
sa=0 sb=0 sd=0
model=pfet_01v8
spiceprefix=X
}
C {madvlsi/nmos3.sym} 700 560 3 1 {name=M4
L=0.5
W=12
body=GND
nf=1
mult=1
ad="'int((nf+1)/2) * W/nf * 0.29'" 
pd="'2*int((nf+1)/2) * (W/nf + 0.29)'"
as="'int((nf+2)/2) * W/nf * 0.29'" 
ps="'2*int((nf+2)/2) * (W/nf + 0.29)'"
nrd="'0.29 / W'" nrs="'0.29 / W'"
sa=0 sb=0 sd=0
model=nfet_01v8
spiceprefix=X
}
C {madvlsi/vdd.sym} 700 340 0 1 {name=l3 lab=VDD}
C {madvlsi/gnd.sym} 660 560 0 1 {name=l4 lab=GND}
C {madvlsi/pmos3.sym} 780 -40 3 1 {name=M5
L=0.5
W=12
body=VDD
nf=1
mult=1
ad="'int((nf+1)/2) * W/nf * 0.29'" 
pd="'2*int((nf+1)/2) * (W/nf + 0.29)'"
as="'int((nf+2)/2) * W/nf * 0.29'" 
ps="'2*int((nf+2)/2) * (W/nf + 0.29)'"
nrd="'0.29 / W'" nrs="'0.29 / W'"
sa=0 sb=0 sd=0
model=pfet_01v8
spiceprefix=X
}
C {madvlsi/nmos3.sym} 780 140 3 1 {name=M6
L=0.5
W=12
body=GND
nf=1
mult=1
ad="'int((nf+1)/2) * W/nf * 0.29'" 
pd="'2*int((nf+1)/2) * (W/nf + 0.29)'"
as="'int((nf+2)/2) * W/nf * 0.29'" 
ps="'2*int((nf+2)/2) * (W/nf + 0.29)'"
nrd="'0.29 / W'" nrs="'0.29 / W'"
sa=0 sb=0 sd=0
model=nfet_01v8
spiceprefix=X
}
C {madvlsi/vdd.sym} 740 -80 0 1 {name=l5 lab=VDD}
C {madvlsi/gnd.sym} 740 140 0 1 {name=l6 lab=GND}
C {madvlsi/pmos3.sym} 2090 -40 1 0 {name=M8
L=0.5
W=12
body=VDD
nf=1
mult=1
ad="'int((nf+1)/2) * W/nf * 0.29'" 
pd="'2*int((nf+1)/2) * (W/nf + 0.29)'"
as="'int((nf+2)/2) * W/nf * 0.29'" 
ps="'2*int((nf+2)/2) * (W/nf + 0.29)'"
nrd="'0.29 / W'" nrs="'0.29 / W'"
sa=0 sb=0 sd=0
model=pfet_01v8
spiceprefix=X
}
C {madvlsi/nmos3.sym} 2090 140 1 0 {name=M9
L=0.5
W=12
body=GND
nf=1
mult=1
ad="'int((nf+1)/2) * W/nf * 0.29'" 
pd="'2*int((nf+1)/2) * (W/nf + 0.29)'"
as="'int((nf+2)/2) * W/nf * 0.29'" 
ps="'2*int((nf+2)/2) * (W/nf + 0.29)'"
nrd="'0.29 / W'" nrs="'0.29 / W'"
sa=0 sb=0 sd=0
model=nfet_01v8
spiceprefix=X
}
C {madvlsi/vdd.sym} 2130 -80 0 0 {name=l7 lab=VDD}
C {madvlsi/gnd.sym} 2130 140 0 0 {name=l8 lab=GND}
C {madvlsi/nmos3.sym} 1890 560 1 0 {name=M10
L=0.5
W=12
body=GND
nf=1
mult=1
ad="'int((nf+1)/2) * W/nf * 0.29'" 
pd="'2*int((nf+1)/2) * (W/nf + 0.29)'"
as="'int((nf+2)/2) * W/nf * 0.29'" 
ps="'2*int((nf+2)/2) * (W/nf + 0.29)'"
nrd="'0.29 / W'" nrs="'0.29 / W'"
sa=0 sb=0 sd=0
model=nfet_01v8
spiceprefix=X
}
C {madvlsi/nmos3.sym} 880 560 1 0 {name=M11
L=0.5
W=12
body=GND
nf=1
mult=1
ad="'int((nf+1)/2) * W/nf * 0.29'" 
pd="'2*int((nf+1)/2) * (W/nf + 0.29)'"
as="'int((nf+2)/2) * W/nf * 0.29'" 
ps="'2*int((nf+2)/2) * (W/nf + 0.29)'"
nrd="'0.29 / W'" nrs="'0.29 / W'"
sa=0 sb=0 sd=0
model=nfet_01v8
spiceprefix=X
}
C {madvlsi/gnd.sym} 1920 220 0 0 {name=l11 lab=GND}
C {madvlsi/vdd.sym} 1910 -190 0 0 {name=l15 lab=VDD}
